VERSION 5.7 ;
  NOWIREEXTENSIONATPIN ON ;
  DIVIDERCHAR "/" ;
  BUSBITCHARS "[]" ;
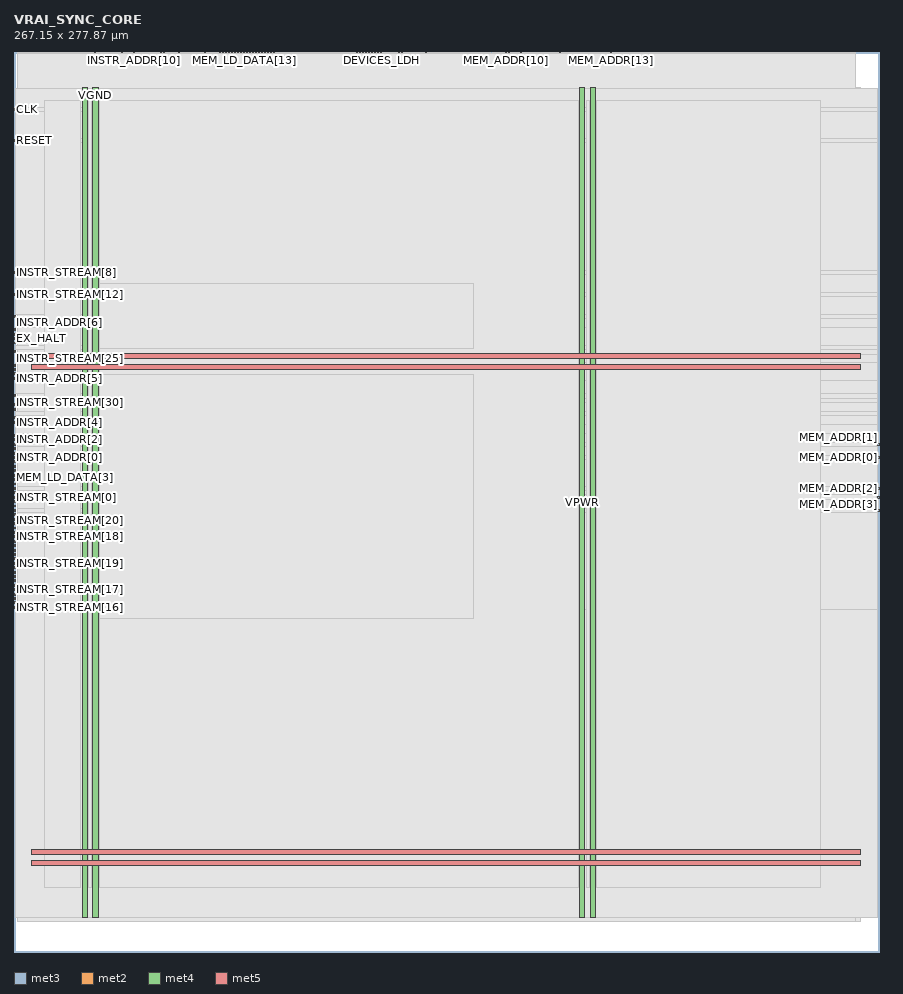
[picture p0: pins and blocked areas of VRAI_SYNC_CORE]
MACRO VRAI_SYNC_CORE
  CLASS BLOCK ;
  FOREIGN VRAI_SYNC_CORE ;
  ORIGIN 0.000 0.000 ;
  SIZE 267.150 BY 277.870 ;
  PIN CLK
    DIRECTION INPUT ;
    USE SIGNAL ;
    ANTENNAGATEAREA 0.852000 ;
    PORT
      LAYER met3 ;
        RECT 0.000 259.800 0.600 260.400 ;
    END
  END CLK
  PIN DEVICES_LDH
    DIRECTION OUTPUT ;
    USE SIGNAL ;
    ANTENNADIFFAREA 0.702900 ;
    PORT
      LAYER met2 ;
        RECT 113.250 277.590 113.530 277.870 ;
    END
  END DEVICES_LDH
  PIN DEVICES_LDW
    DIRECTION OUTPUT ;
    USE SIGNAL ;
    ANTENNADIFFAREA 0.702900 ;
    PORT
      LAYER met2 ;
        RECT 109.570 277.590 109.850 277.870 ;
    END
  END DEVICES_LDW
  PIN DEVICES_STRH
    DIRECTION OUTPUT ;
    USE SIGNAL ;
    ANTENNADIFFAREA 0.702900 ;
    PORT
      LAYER met2 ;
        RECT 112.330 277.590 112.610 277.870 ;
    END
  END DEVICES_STRH
  PIN DEVICES_STRW
    DIRECTION OUTPUT ;
    USE SIGNAL ;
    ANTENNADIFFAREA 0.702900 ;
    PORT
      LAYER met2 ;
        RECT 111.410 277.590 111.690 277.870 ;
    END
  END DEVICES_STRW
  PIN EX_HALT
    DIRECTION OUTPUT ;
    USE SIGNAL ;
    ANTENNADIFFAREA 0.702900 ;
    PORT
      LAYER met3 ;
        RECT 0.000 189.080 0.600 189.680 ;
    END
  END EX_HALT
  PIN INSTR_ADDR[0]
    DIRECTION OUTPUT ;
    USE SIGNAL ;
    ANTENNADIFFAREA 0.702900 ;
    PORT
      LAYER met3 ;
        RECT 0.000 152.360 0.600 152.960 ;
    END
  END INSTR_ADDR[0]
  PIN INSTR_ADDR[10]
    DIRECTION OUTPUT ;
    USE SIGNAL ;
    ANTENNADIFFAREA 0.702900 ;
    PORT
      LAYER met2 ;
        RECT 36.890 277.590 37.170 277.870 ;
    END
  END INSTR_ADDR[10]
  PIN INSTR_ADDR[11]
    DIRECTION OUTPUT ;
    USE SIGNAL ;
    ANTENNADIFFAREA 0.702900 ;
    PORT
      LAYER met2 ;
        RECT 50.690 277.590 50.970 277.870 ;
    END
  END INSTR_ADDR[11]
  PIN INSTR_ADDR[12]
    DIRECTION OUTPUT ;
    USE SIGNAL ;
    ANTENNADIFFAREA 0.702900 ;
    PORT
      LAYER met2 ;
        RECT 58.970 277.590 59.250 277.870 ;
    END
  END INSTR_ADDR[12]
  PIN INSTR_ADDR[13]
    DIRECTION OUTPUT ;
    USE SIGNAL ;
    ANTENNADIFFAREA 0.702900 ;
    PORT
      LAYER met2 ;
        RECT 64.490 277.590 64.770 277.870 ;
    END
  END INSTR_ADDR[13]
  PIN INSTR_ADDR[14]
    DIRECTION OUTPUT ;
    USE SIGNAL ;
    ANTENNADIFFAREA 0.702900 ;
    PORT
      LAYER met2 ;
        RECT 65.410 277.590 65.690 277.870 ;
    END
  END INSTR_ADDR[14]
  PIN INSTR_ADDR[15]
    DIRECTION OUTPUT ;
    USE SIGNAL ;
    ANTENNADIFFAREA 0.702900 ;
    PORT
      LAYER met2 ;
        RECT 63.570 277.590 63.850 277.870 ;
    END
  END INSTR_ADDR[15]
  PIN INSTR_ADDR[1]
    DIRECTION OUTPUT ;
    USE SIGNAL ;
    ANTENNADIFFAREA 0.702900 ;
    PORT
      LAYER met3 ;
        RECT 0.000 151.000 0.600 151.600 ;
    END
  END INSTR_ADDR[1]
  PIN INSTR_ADDR[2]
    DIRECTION OUTPUT ;
    USE SIGNAL ;
    ANTENNADIFFAREA 0.702900 ;
    PORT
      LAYER met3 ;
        RECT 0.000 157.800 0.600 158.400 ;
    END
  END INSTR_ADDR[2]
  PIN INSTR_ADDR[3]
    DIRECTION OUTPUT ;
    USE SIGNAL ;
    ANTENNADIFFAREA 0.702900 ;
    PORT
      LAYER met3 ;
        RECT 0.000 155.080 0.600 155.680 ;
    END
  END INSTR_ADDR[3]
  PIN INSTR_ADDR[4]
    DIRECTION OUTPUT ;
    USE SIGNAL ;
    ANTENNADIFFAREA 0.702900 ;
    PORT
      LAYER met3 ;
        RECT 0.000 163.240 0.600 163.840 ;
    END
  END INSTR_ADDR[4]
  PIN INSTR_ADDR[5]
    DIRECTION OUTPUT ;
    USE SIGNAL ;
    ANTENNADIFFAREA 0.702900 ;
    PORT
      LAYER met3 ;
        RECT 0.000 176.840 0.600 177.440 ;
    END
  END INSTR_ADDR[5]
  PIN INSTR_ADDR[6]
    DIRECTION OUTPUT ;
    USE SIGNAL ;
    ANTENNADIFFAREA 0.702900 ;
    PORT
      LAYER met3 ;
        RECT 0.000 191.800 0.600 192.400 ;
    END
  END INSTR_ADDR[6]
  PIN INSTR_ADDR[7]
    DIRECTION OUTPUT ;
    USE SIGNAL ;
    ANTENNADIFFAREA 0.702900 ;
    PORT
      LAYER met3 ;
        RECT 0.000 195.880 0.600 196.480 ;
    END
  END INSTR_ADDR[7]
  PIN INSTR_ADDR[8]
    DIRECTION OUTPUT ;
    USE SIGNAL ;
    ANTENNADIFFAREA 0.702900 ;
    PORT
      LAYER met2 ;
        RECT 24.930 277.590 25.210 277.870 ;
    END
  END INSTR_ADDR[8]
  PIN INSTR_ADDR[9]
    DIRECTION OUTPUT ;
    USE SIGNAL ;
    ANTENNADIFFAREA 0.702900 ;
    PORT
      LAYER met2 ;
        RECT 33.210 277.590 33.490 277.870 ;
    END
  END INSTR_ADDR[9]
  PIN INSTR_STREAM[0]
    DIRECTION INPUT ;
    USE SIGNAL ;
    ANTENNAGATEAREA 0.213000 ;
    PORT
      LAYER met3 ;
        RECT 0.000 140.120 0.600 140.720 ;
    END
  END INSTR_STREAM[0]
  PIN INSTR_STREAM[10]
    DIRECTION INPUT ;
    USE SIGNAL ;
    ANTENNAGATEAREA 0.213000 ;
    PORT
      LAYER met2 ;
        RECT 66.330 277.590 66.610 277.870 ;
    END
  END INSTR_STREAM[10]
  PIN INSTR_STREAM[11]
    DIRECTION INPUT ;
    USE SIGNAL ;
    ANTENNAGATEAREA 0.213000 ;
    PORT
      LAYER met2 ;
        RECT 71.850 277.590 72.130 277.870 ;
    END
  END INSTR_STREAM[11]
  PIN INSTR_STREAM[12]
    DIRECTION INPUT ;
    USE SIGNAL ;
    ANTENNAGATEAREA 0.213000 ;
    PORT
      LAYER met3 ;
        RECT 0.000 202.680 0.600 203.280 ;
    END
  END INSTR_STREAM[12]
  PIN INSTR_STREAM[13]
    DIRECTION INPUT ;
    USE SIGNAL ;
    ANTENNAGATEAREA 0.213000 ;
    PORT
      LAYER met2 ;
        RECT 67.250 277.590 67.530 277.870 ;
    END
  END INSTR_STREAM[13]
  PIN INSTR_STREAM[14]
    DIRECTION INPUT ;
    USE SIGNAL ;
    ANTENNAGATEAREA 0.213000 ;
    PORT
      LAYER met3 ;
        RECT 0.000 187.720 0.600 188.320 ;
    END
  END INSTR_STREAM[14]
  PIN INSTR_STREAM[15]
    DIRECTION INPUT ;
    USE SIGNAL ;
    ANTENNAGATEAREA 0.213000 ;
    PORT
      LAYER met2 ;
        RECT 76.450 277.590 76.730 277.870 ;
    END
  END INSTR_STREAM[15]
  PIN INSTR_STREAM[16]
    DIRECTION INPUT ;
    USE SIGNAL ;
    ANTENNAGATEAREA 0.213000 ;
    PORT
      LAYER met3 ;
        RECT 0.000 106.120 0.600 106.720 ;
    END
  END INSTR_STREAM[16]
  PIN INSTR_STREAM[17]
    DIRECTION INPUT ;
    USE SIGNAL ;
    ANTENNAGATEAREA 0.213000 ;
    PORT
      LAYER met3 ;
        RECT 0.000 111.560 0.600 112.160 ;
    END
  END INSTR_STREAM[17]
  PIN INSTR_STREAM[18]
    DIRECTION INPUT ;
    USE SIGNAL ;
    ANTENNAGATEAREA 0.213000 ;
    PORT
      LAYER met3 ;
        RECT 0.000 127.880 0.600 128.480 ;
    END
  END INSTR_STREAM[18]
  PIN INSTR_STREAM[19]
    DIRECTION INPUT ;
    USE SIGNAL ;
    ANTENNAGATEAREA 0.213000 ;
    PORT
      LAYER met3 ;
        RECT 0.000 119.720 0.600 120.320 ;
    END
  END INSTR_STREAM[19]
  PIN INSTR_STREAM[1]
    DIRECTION INPUT ;
    USE SIGNAL ;
    ANTENNAGATEAREA 0.213000 ;
    PORT
      LAYER met3 ;
        RECT 0.000 129.240 0.600 129.840 ;
    END
  END INSTR_STREAM[1]
  PIN INSTR_STREAM[20]
    DIRECTION INPUT ;
    USE SIGNAL ;
    ANTENNAGATEAREA 0.213000 ;
    PORT
      LAYER met3 ;
        RECT 0.000 130.600 0.600 131.200 ;
    END
  END INSTR_STREAM[20]
  PIN INSTR_STREAM[21]
    DIRECTION INPUT ;
    USE SIGNAL ;
    ANTENNAGATEAREA 0.213000 ;
    PORT
      LAYER met3 ;
        RECT 0.000 131.960 0.600 132.560 ;
    END
  END INSTR_STREAM[21]
  PIN INSTR_STREAM[22]
    DIRECTION INPUT ;
    USE SIGNAL ;
    ANTENNAGATEAREA 0.213000 ;
    PORT
      LAYER met3 ;
        RECT 0.000 125.160 0.600 125.760 ;
    END
  END INSTR_STREAM[22]
  PIN INSTR_STREAM[23]
    DIRECTION INPUT ;
    USE SIGNAL ;
    ANTENNAGATEAREA 0.213000 ;
    PORT
      LAYER met3 ;
        RECT 0.000 136.040 0.600 136.640 ;
    END
  END INSTR_STREAM[23]
  PIN INSTR_STREAM[24]
    DIRECTION INPUT ;
    USE SIGNAL ;
    ANTENNAGATEAREA 0.213000 ;
    PORT
      LAYER met2 ;
        RECT 73.690 277.590 73.970 277.870 ;
    END
  END INSTR_STREAM[24]
  PIN INSTR_STREAM[25]
    DIRECTION INPUT ;
    USE SIGNAL ;
    ANTENNAGATEAREA 0.213000 ;
    PORT
      LAYER met3 ;
        RECT 0.000 185.000 0.600 185.600 ;
    END
  END INSTR_STREAM[25]
  PIN INSTR_STREAM[26]
    DIRECTION INPUT ;
    USE SIGNAL ;
    ANTENNAGATEAREA 0.213000 ;
    PORT
      LAYER met2 ;
        RECT 74.610 277.590 74.890 277.870 ;
    END
  END INSTR_STREAM[26]
  PIN INSTR_STREAM[27]
    DIRECTION INPUT ;
    USE SIGNAL ;
    ANTENNAGATEAREA 0.213000 ;
    PORT
      LAYER met2 ;
        RECT 72.770 277.590 73.050 277.870 ;
    END
  END INSTR_STREAM[27]
  PIN INSTR_STREAM[28]
    DIRECTION INPUT ;
    USE SIGNAL ;
    ANTENNAGATEAREA 0.213000 ;
    PORT
      LAYER met3 ;
        RECT 0.000 159.160 0.600 159.760 ;
    END
  END INSTR_STREAM[28]
  PIN INSTR_STREAM[29]
    DIRECTION INPUT ;
    USE SIGNAL ;
    ANTENNAGATEAREA 0.213000 ;
    PORT
      LAYER met3 ;
        RECT 0.000 156.440 0.600 157.040 ;
    END
  END INSTR_STREAM[29]
  PIN INSTR_STREAM[2]
    DIRECTION INPUT ;
    USE SIGNAL ;
    ANTENNAGATEAREA 0.213000 ;
    PORT
      LAYER met3 ;
        RECT 0.000 138.760 0.600 139.360 ;
    END
  END INSTR_STREAM[2]
  PIN INSTR_STREAM[30]
    DIRECTION INPUT ;
    USE SIGNAL ;
    ANTENNAGATEAREA 0.213000 ;
    PORT
      LAYER met3 ;
        RECT 0.000 167.320 0.600 167.920 ;
    END
  END INSTR_STREAM[30]
  PIN INSTR_STREAM[31]
    DIRECTION INPUT ;
    USE SIGNAL ;
    ANTENNAGATEAREA 0.213000 ;
    PORT
      LAYER met3 ;
        RECT 0.000 164.600 0.600 165.200 ;
    END
  END INSTR_STREAM[31]
  PIN INSTR_STREAM[3]
    DIRECTION INPUT ;
    USE SIGNAL ;
    ANTENNAGATEAREA 0.213000 ;
    PORT
      LAYER met3 ;
        RECT 0.000 137.400 0.600 138.000 ;
    END
  END INSTR_STREAM[3]
  PIN INSTR_STREAM[4]
    DIRECTION INPUT ;
    USE SIGNAL ;
    ANTENNAGATEAREA 0.213000 ;
    PORT
      LAYER met3 ;
        RECT 0.000 149.640 0.600 150.240 ;
    END
  END INSTR_STREAM[4]
  PIN INSTR_STREAM[5]
    DIRECTION INPUT ;
    USE SIGNAL ;
    ANTENNAGATEAREA 0.213000 ;
    PORT
      LAYER met3 ;
        RECT 0.000 178.200 0.600 178.800 ;
    END
  END INSTR_STREAM[5]
  PIN INSTR_STREAM[6]
    DIRECTION INPUT ;
    USE SIGNAL ;
    ANTENNAGATEAREA 0.213000 ;
    PORT
      LAYER met2 ;
        RECT 46.090 277.590 46.370 277.870 ;
    END
  END INSTR_STREAM[6]
  PIN INSTR_STREAM[7]
    DIRECTION INPUT ;
    USE SIGNAL ;
    ANTENNAGATEAREA 0.213000 ;
    PORT
      LAYER met3 ;
        RECT 0.000 190.440 0.600 191.040 ;
    END
  END INSTR_STREAM[7]
  PIN INSTR_STREAM[8]
    DIRECTION INPUT ;
    USE SIGNAL ;
    ANTENNAGATEAREA 0.213000 ;
    PORT
      LAYER met3 ;
        RECT 0.000 209.480 0.600 210.080 ;
    END
  END INSTR_STREAM[8]
  PIN INSTR_STREAM[9]
    DIRECTION INPUT ;
    USE SIGNAL ;
    ANTENNAGATEAREA 0.213000 ;
    PORT
      LAYER met2 ;
        RECT 45.170 277.590 45.450 277.870 ;
    END
  END INSTR_STREAM[9]
  PIN INVALID_MEM
    DIRECTION OUTPUT ;
    USE SIGNAL ;
    ANTENNADIFFAREA 0.702900 ;
    PORT
      LAYER met3 ;
        RECT 0.000 180.920 0.600 181.520 ;
    END
  END INVALID_MEM
  PIN MAIN_LDH
    DIRECTION OUTPUT ;
    USE SIGNAL ;
    ANTENNADIFFAREA 0.702900 ;
    PORT
      LAYER met2 ;
        RECT 105.890 277.590 106.170 277.870 ;
    END
  END MAIN_LDH
  PIN MAIN_LDW
    DIRECTION OUTPUT ;
    USE SIGNAL ;
    ANTENNADIFFAREA 0.702900 ;
    PORT
      LAYER met2 ;
        RECT 106.810 277.590 107.090 277.870 ;
    END
  END MAIN_LDW
  PIN MAIN_STRH
    DIRECTION OUTPUT ;
    USE SIGNAL ;
    ANTENNADIFFAREA 0.702900 ;
    PORT
      LAYER met2 ;
        RECT 108.650 277.590 108.930 277.870 ;
    END
  END MAIN_STRH
  PIN MAIN_STRW
    DIRECTION OUTPUT ;
    USE SIGNAL ;
    ANTENNADIFFAREA 0.702900 ;
    PORT
      LAYER met2 ;
        RECT 107.730 277.590 108.010 277.870 ;
    END
  END MAIN_STRW
  PIN MEM_ADDR[0]
    DIRECTION OUTPUT ;
    USE SIGNAL ;
    ANTENNADIFFAREA 0.702900 ;
    PORT
      LAYER met3 ;
        RECT 266.550 152.360 267.150 152.960 ;
    END
  END MEM_ADDR[0]
  PIN MEM_ADDR[10]
    DIRECTION OUTPUT ;
    USE SIGNAL ;
    ANTENNADIFFAREA 0.702900 ;
    PORT
      LAYER met2 ;
        RECT 151.890 277.590 152.170 277.870 ;
    END
  END MEM_ADDR[10]
  PIN MEM_ADDR[11]
    DIRECTION OUTPUT ;
    USE SIGNAL ;
    ANTENNADIFFAREA 0.702900 ;
    PORT
      LAYER met2 ;
        RECT 127.050 277.590 127.330 277.870 ;
    END
  END MEM_ADDR[11]
  PIN MEM_ADDR[12]
    DIRECTION OUTPUT ;
    USE SIGNAL ;
    ANTENNADIFFAREA 0.702900 ;
    PORT
      LAYER met2 ;
        RECT 156.490 277.590 156.770 277.870 ;
    END
  END MEM_ADDR[12]
  PIN MEM_ADDR[13]
    DIRECTION OUTPUT ;
    USE SIGNAL ;
    ANTENNADIFFAREA 0.702900 ;
    PORT
      LAYER met2 ;
        RECT 184.090 277.590 184.370 277.870 ;
    END
  END MEM_ADDR[13]
  PIN MEM_ADDR[14]
    DIRECTION OUTPUT ;
    USE SIGNAL ;
    ANTENNADIFFAREA 0.702900 ;
    PORT
      LAYER met2 ;
        RECT 168.450 277.590 168.730 277.870 ;
    END
  END MEM_ADDR[14]
  PIN MEM_ADDR[15]
    DIRECTION OUTPUT ;
    USE SIGNAL ;
    ANTENNADIFFAREA 0.702900 ;
    PORT
      LAYER met2 ;
        RECT 110.490 277.590 110.770 277.870 ;
    END
  END MEM_ADDR[15]
  PIN MEM_ADDR[1]
    DIRECTION OUTPUT ;
    USE SIGNAL ;
    ANTENNADIFFAREA 0.702900 ;
    PORT
      LAYER met3 ;
        RECT 266.550 156.440 267.150 157.040 ;
    END
  END MEM_ADDR[1]
  PIN MEM_ADDR[2]
    DIRECTION OUTPUT ;
    USE SIGNAL ;
    ANTENNADIFFAREA 0.702900 ;
    PORT
      LAYER met3 ;
        RECT 266.550 142.840 267.150 143.440 ;
    END
  END MEM_ADDR[2]
  PIN MEM_ADDR[3]
    DIRECTION OUTPUT ;
    USE SIGNAL ;
    ANTENNADIFFAREA 0.702900 ;
    PORT
      LAYER met3 ;
        RECT 266.550 140.120 267.150 140.720 ;
    END
  END MEM_ADDR[3]
  PIN MEM_ADDR[4]
    DIRECTION OUTPUT ;
    USE SIGNAL ;
    ANTENNADIFFAREA 0.702900 ;
    PORT
      LAYER met3 ;
        RECT 266.550 136.040 267.150 136.640 ;
    END
  END MEM_ADDR[4]
  PIN MEM_ADDR[5]
    DIRECTION OUTPUT ;
    USE SIGNAL ;
    ANTENNADIFFAREA 0.702900 ;
    PORT
      LAYER met3 ;
        RECT 0.000 153.720 0.600 154.320 ;
    END
  END MEM_ADDR[5]
  PIN MEM_ADDR[6]
    DIRECTION OUTPUT ;
    USE SIGNAL ;
    ANTENNADIFFAREA 0.702900 ;
    PORT
      LAYER met2 ;
        RECT 147.290 277.590 147.570 277.870 ;
    END
  END MEM_ADDR[6]
  PIN MEM_ADDR[7]
    DIRECTION OUTPUT ;
    USE SIGNAL ;
    ANTENNADIFFAREA 0.702900 ;
    PORT
      LAYER met2 ;
        RECT 119.690 277.590 119.970 277.870 ;
    END
  END MEM_ADDR[7]
  PIN MEM_ADDR[8]
    DIRECTION OUTPUT ;
    USE SIGNAL ;
    ANTENNADIFFAREA 0.702900 ;
    PORT
      LAYER met2 ;
        RECT 118.770 277.590 119.050 277.870 ;
    END
  END MEM_ADDR[8]
  PIN MEM_ADDR[9]
    DIRECTION OUTPUT ;
    USE SIGNAL ;
    ANTENNADIFFAREA 0.702900 ;
    PORT
      LAYER met2 ;
        RECT 152.810 277.590 153.090 277.870 ;
    END
  END MEM_ADDR[9]
  PIN MEM_LD_DATA[0]
    DIRECTION INPUT ;
    USE SIGNAL ;
    ANTENNAGATEAREA 0.213000 ;
    PORT
      LAYER met3 ;
        RECT 0.000 144.200 0.600 144.800 ;
    END
  END MEM_LD_DATA[0]
  PIN MEM_LD_DATA[10]
    DIRECTION INPUT ;
    USE SIGNAL ;
    ANTENNAGATEAREA 0.213000 ;
    PORT
      LAYER met2 ;
        RECT 77.370 277.590 77.650 277.870 ;
    END
  END MEM_LD_DATA[10]
  PIN MEM_LD_DATA[11]
    DIRECTION INPUT ;
    USE SIGNAL ;
    ANTENNAGATEAREA 0.213000 ;
    PORT
      LAYER met2 ;
        RECT 75.530 277.590 75.810 277.870 ;
    END
  END MEM_LD_DATA[11]
  PIN MEM_LD_DATA[12]
    DIRECTION INPUT ;
    USE SIGNAL ;
    ANTENNAGATEAREA 0.213000 ;
    PORT
      LAYER met2 ;
        RECT 68.170 277.590 68.450 277.870 ;
    END
  END MEM_LD_DATA[12]
  PIN MEM_LD_DATA[13]
    DIRECTION INPUT ;
    USE SIGNAL ;
    ANTENNAGATEAREA 0.213000 ;
    PORT
      LAYER met2 ;
        RECT 70.930 277.590 71.210 277.870 ;
    END
  END MEM_LD_DATA[13]
  PIN MEM_LD_DATA[14]
    DIRECTION INPUT ;
    USE SIGNAL ;
    ANTENNAGATEAREA 0.213000 ;
    PORT
      LAYER met2 ;
        RECT 79.210 277.590 79.490 277.870 ;
    END
  END MEM_LD_DATA[14]
  PIN MEM_LD_DATA[15]
    DIRECTION INPUT ;
    USE SIGNAL ;
    ANTENNAGATEAREA 0.213000 ;
    PORT
      LAYER met2 ;
        RECT 80.130 277.590 80.410 277.870 ;
    END
  END MEM_LD_DATA[15]
  PIN MEM_LD_DATA[1]
    DIRECTION INPUT ;
    USE SIGNAL ;
    ANTENNAGATEAREA 0.213000 ;
    PORT
      LAYER met3 ;
        RECT 0.000 146.920 0.600 147.520 ;
    END
  END MEM_LD_DATA[1]
  PIN MEM_LD_DATA[2]
    DIRECTION INPUT ;
    USE SIGNAL ;
    ANTENNAGATEAREA 0.213000 ;
    PORT
      LAYER met3 ;
        RECT 0.000 171.400 0.600 172.000 ;
    END
  END MEM_LD_DATA[2]
  PIN MEM_LD_DATA[3]
    DIRECTION INPUT ;
    USE SIGNAL ;
    ANTENNAGATEAREA 0.213000 ;
    PORT
      LAYER met3 ;
        RECT 0.000 148.280 0.600 148.880 ;
    END
  END MEM_LD_DATA[3]
  PIN MEM_LD_DATA[4]
    DIRECTION INPUT ;
    USE SIGNAL ;
    ANTENNAGATEAREA 0.213000 ;
    PORT
      LAYER met3 ;
        RECT 0.000 145.560 0.600 146.160 ;
    END
  END MEM_LD_DATA[4]
  PIN MEM_LD_DATA[5]
    DIRECTION INPUT ;
    USE SIGNAL ;
    ANTENNAGATEAREA 0.213000 ;
    PORT
      LAYER met3 ;
        RECT 0.000 168.680 0.600 169.280 ;
    END
  END MEM_LD_DATA[5]
  PIN MEM_LD_DATA[6]
    DIRECTION INPUT ;
    USE SIGNAL ;
    ANTENNAGATEAREA 0.213000 ;
    PORT
      LAYER met3 ;
        RECT 0.000 179.560 0.600 180.160 ;
    END
  END MEM_LD_DATA[6]
  PIN MEM_LD_DATA[7]
    DIRECTION INPUT ;
    USE SIGNAL ;
    ANTENNAGATEAREA 0.213000 ;
    PORT
      LAYER met2 ;
        RECT 70.010 277.590 70.290 277.870 ;
    END
  END MEM_LD_DATA[7]
  PIN MEM_LD_DATA[8]
    DIRECTION INPUT ;
    USE SIGNAL ;
    ANTENNAGATEAREA 0.213000 ;
    PORT
      LAYER met2 ;
        RECT 78.290 277.590 78.570 277.870 ;
    END
  END MEM_LD_DATA[8]
  PIN MEM_LD_DATA[9]
    DIRECTION INPUT ;
    USE SIGNAL ;
    ANTENNAGATEAREA 0.213000 ;
    PORT
      LAYER met2 ;
        RECT 69.090 277.590 69.370 277.870 ;
    END
  END MEM_LD_DATA[9]
  PIN MEM_STR_DATA[0]
    DIRECTION OUTPUT ;
    USE SIGNAL ;
    ANTENNADIFFAREA 0.702900 ;
    PORT
      LAYER met3 ;
        RECT 0.000 108.840 0.600 109.440 ;
    END
  END MEM_STR_DATA[0]
  PIN MEM_STR_DATA[10]
    DIRECTION OUTPUT ;
    USE SIGNAL ;
    ANTENNADIFFAREA 0.702900 ;
    PORT
      LAYER met3 ;
        RECT 0.000 115.640 0.600 116.240 ;
    END
  END MEM_STR_DATA[10]
  PIN MEM_STR_DATA[11]
    DIRECTION OUTPUT ;
    USE SIGNAL ;
    ANTENNADIFFAREA 0.702900 ;
    PORT
      LAYER met3 ;
        RECT 0.000 117.000 0.600 117.600 ;
    END
  END MEM_STR_DATA[11]
  PIN MEM_STR_DATA[12]
    DIRECTION OUTPUT ;
    USE SIGNAL ;
    ANTENNADIFFAREA 0.702900 ;
    PORT
      LAYER met3 ;
        RECT 0.000 110.200 0.600 110.800 ;
    END
  END MEM_STR_DATA[12]
  PIN MEM_STR_DATA[13]
    DIRECTION OUTPUT ;
    USE SIGNAL ;
    ANTENNADIFFAREA 0.702900 ;
    PORT
      LAYER met3 ;
        RECT 0.000 133.320 0.600 133.920 ;
    END
  END MEM_STR_DATA[13]
  PIN MEM_STR_DATA[14]
    DIRECTION OUTPUT ;
    USE SIGNAL ;
    ANTENNADIFFAREA 0.702900 ;
    PORT
      LAYER met3 ;
        RECT 0.000 134.680 0.600 135.280 ;
    END
  END MEM_STR_DATA[14]
  PIN MEM_STR_DATA[15]
    DIRECTION OUTPUT ;
    USE SIGNAL ;
    ANTENNADIFFAREA 0.702900 ;
    PORT
      LAYER met3 ;
        RECT 0.000 122.440 0.600 123.040 ;
    END
  END MEM_STR_DATA[15]
  PIN MEM_STR_DATA[1]
    DIRECTION OUTPUT ;
    USE SIGNAL ;
    ANTENNADIFFAREA 0.702900 ;
    PORT
      LAYER met3 ;
        RECT 0.000 114.280 0.600 114.880 ;
    END
  END MEM_STR_DATA[1]
  PIN MEM_STR_DATA[2]
    DIRECTION OUTPUT ;
    USE SIGNAL ;
    ANTENNADIFFAREA 0.702900 ;
    PORT
      LAYER met3 ;
        RECT 0.000 142.840 0.600 143.440 ;
    END
  END MEM_STR_DATA[2]
  PIN MEM_STR_DATA[3]
    DIRECTION OUTPUT ;
    USE SIGNAL ;
    ANTENNADIFFAREA 0.702900 ;
    PORT
      LAYER met3 ;
        RECT 0.000 121.080 0.600 121.680 ;
    END
  END MEM_STR_DATA[3]
  PIN MEM_STR_DATA[4]
    DIRECTION OUTPUT ;
    USE SIGNAL ;
    ANTENNADIFFAREA 0.702900 ;
    PORT
      LAYER met3 ;
        RECT 0.000 118.360 0.600 118.960 ;
    END
  END MEM_STR_DATA[4]
  PIN MEM_STR_DATA[5]
    DIRECTION OUTPUT ;
    USE SIGNAL ;
    ANTENNADIFFAREA 0.702900 ;
    PORT
      LAYER met3 ;
        RECT 0.000 123.800 0.600 124.400 ;
    END
  END MEM_STR_DATA[5]
  PIN MEM_STR_DATA[6]
    DIRECTION OUTPUT ;
    USE SIGNAL ;
    ANTENNADIFFAREA 0.702900 ;
    PORT
      LAYER met3 ;
        RECT 0.000 141.480 0.600 142.080 ;
    END
  END MEM_STR_DATA[6]
  PIN MEM_STR_DATA[7]
    DIRECTION OUTPUT ;
    USE SIGNAL ;
    ANTENNADIFFAREA 0.702900 ;
    PORT
      LAYER met3 ;
        RECT 0.000 112.920 0.600 113.520 ;
    END
  END MEM_STR_DATA[7]
  PIN MEM_STR_DATA[8]
    DIRECTION OUTPUT ;
    USE SIGNAL ;
    ANTENNADIFFAREA 0.702900 ;
    PORT
      LAYER met3 ;
        RECT 0.000 107.480 0.600 108.080 ;
    END
  END MEM_STR_DATA[8]
  PIN MEM_STR_DATA[9]
    DIRECTION OUTPUT ;
    USE SIGNAL ;
    ANTENNADIFFAREA 0.702900 ;
    PORT
      LAYER met3 ;
        RECT 0.000 126.520 0.600 127.120 ;
    END
  END MEM_STR_DATA[9]
  PIN RESET
    DIRECTION INPUT ;
    USE SIGNAL ;
    ANTENNAGATEAREA 0.247500 ;
    PORT
      LAYER met3 ;
        RECT 0.000 250.280 0.600 250.880 ;
    END
  END RESET
  PIN VGND
    DIRECTION INOUT ;
    USE GROUND ;
    PORT
      LAYER met4 ;
        RECT 24.340 10.640 25.940 266.800 ;
    END
    PORT
      LAYER met4 ;
        RECT 177.940 10.640 179.540 266.800 ;
    END
    PORT
      LAYER met5 ;
        RECT 5.520 30.030 261.280 31.630 ;
    END
    PORT
      LAYER met5 ;
        RECT 5.520 183.210 261.280 184.810 ;
    END
  END VGND
  PIN VPWR
    DIRECTION INOUT ;
    USE POWER ;
    PORT
      LAYER met4 ;
        RECT 21.040 10.640 22.640 266.800 ;
    END
    PORT
      LAYER met4 ;
        RECT 174.640 10.640 176.240 266.800 ;
    END
    PORT
      LAYER met5 ;
        RECT 5.520 26.730 261.280 28.330 ;
    END
    PORT
      LAYER met5 ;
        RECT 5.520 179.910 261.280 181.510 ;
    END
  END VPWR
  OBS
      LAYER nwell ;
        RECT 5.330 10.795 261.470 266.645 ;
      LAYER li1 ;
        RECT 5.520 10.795 261.280 266.645 ;
      LAYER met1 ;
        RECT 0.990 9.560 261.280 266.800 ;
      LAYER met2 ;
        RECT 1.010 277.310 24.650 277.590 ;
        RECT 25.490 277.310 32.930 277.590 ;
        RECT 33.770 277.310 36.610 277.590 ;
        RECT 37.450 277.310 44.890 277.590 ;
        RECT 45.730 277.310 45.810 277.590 ;
        RECT 46.650 277.310 50.410 277.590 ;
        RECT 51.250 277.310 58.690 277.590 ;
        RECT 59.530 277.310 63.290 277.590 ;
        RECT 64.130 277.310 64.210 277.590 ;
        RECT 65.050 277.310 65.130 277.590 ;
        RECT 65.970 277.310 66.050 277.590 ;
        RECT 66.890 277.310 66.970 277.590 ;
        RECT 67.810 277.310 67.890 277.590 ;
        RECT 68.730 277.310 68.810 277.590 ;
        RECT 69.650 277.310 69.730 277.590 ;
        RECT 70.570 277.310 70.650 277.590 ;
        RECT 71.490 277.310 71.570 277.590 ;
        RECT 72.410 277.310 72.490 277.590 ;
        RECT 73.330 277.310 73.410 277.590 ;
        RECT 74.250 277.310 74.330 277.590 ;
        RECT 75.170 277.310 75.250 277.590 ;
        RECT 76.090 277.310 76.170 277.590 ;
        RECT 77.010 277.310 77.090 277.590 ;
        RECT 77.930 277.310 78.010 277.590 ;
        RECT 78.850 277.310 78.930 277.590 ;
        RECT 79.770 277.310 79.850 277.590 ;
        RECT 80.690 277.310 105.610 277.590 ;
        RECT 106.450 277.310 106.530 277.590 ;
        RECT 107.370 277.310 107.450 277.590 ;
        RECT 108.290 277.310 108.370 277.590 ;
        RECT 109.210 277.310 109.290 277.590 ;
        RECT 110.130 277.310 110.210 277.590 ;
        RECT 111.050 277.310 111.130 277.590 ;
        RECT 111.970 277.310 112.050 277.590 ;
        RECT 112.890 277.310 112.970 277.590 ;
        RECT 113.810 277.310 118.490 277.590 ;
        RECT 119.330 277.310 119.410 277.590 ;
        RECT 120.250 277.310 126.770 277.590 ;
        RECT 127.610 277.310 147.010 277.590 ;
        RECT 147.850 277.310 151.610 277.590 ;
        RECT 152.450 277.310 152.530 277.590 ;
        RECT 153.370 277.310 156.210 277.590 ;
        RECT 157.050 277.310 168.170 277.590 ;
        RECT 169.010 277.310 183.810 277.590 ;
        RECT 184.650 277.310 259.810 277.590 ;
        RECT 1.010 9.530 259.810 277.310 ;
      LAYER met3 ;
        RECT 0.600 260.800 266.550 266.725 ;
        RECT 1.000 259.400 266.550 260.800 ;
        RECT 0.600 251.280 266.550 259.400 ;
        RECT 1.000 249.880 266.550 251.280 ;
        RECT 0.600 210.480 266.550 249.880 ;
        RECT 1.000 209.080 266.550 210.480 ;
        RECT 0.600 203.680 266.550 209.080 ;
        RECT 1.000 202.280 266.550 203.680 ;
        RECT 0.600 196.880 266.550 202.280 ;
        RECT 1.000 195.480 266.550 196.880 ;
        RECT 0.600 192.800 266.550 195.480 ;
        RECT 1.000 187.320 266.550 192.800 ;
        RECT 0.600 186.000 266.550 187.320 ;
        RECT 1.000 184.600 266.550 186.000 ;
        RECT 0.600 181.920 266.550 184.600 ;
        RECT 1.000 176.440 266.550 181.920 ;
        RECT 0.600 172.400 266.550 176.440 ;
        RECT 1.000 171.000 266.550 172.400 ;
        RECT 0.600 169.680 266.550 171.000 ;
        RECT 1.000 166.920 266.550 169.680 ;
        RECT 0.600 165.600 266.550 166.920 ;
        RECT 1.000 162.840 266.550 165.600 ;
        RECT 0.600 160.160 266.550 162.840 ;
        RECT 1.000 157.440 266.550 160.160 ;
        RECT 1.000 156.040 266.150 157.440 ;
        RECT 1.000 153.360 266.550 156.040 ;
        RECT 1.000 151.960 266.150 153.360 ;
        RECT 1.000 143.840 266.550 151.960 ;
        RECT 1.000 142.440 266.150 143.840 ;
        RECT 1.000 141.120 266.550 142.440 ;
        RECT 1.000 139.720 266.150 141.120 ;
        RECT 1.000 137.040 266.550 139.720 ;
        RECT 1.000 135.640 266.150 137.040 ;
        RECT 1.000 105.720 266.550 135.640 ;
        RECT 0.600 10.715 266.550 105.720 ;
      LAYER met4 ;
        RECT 9.495 19.895 20.640 262.985 ;
        RECT 23.040 19.895 23.940 262.985 ;
        RECT 26.340 19.895 174.240 262.985 ;
        RECT 176.640 19.895 177.540 262.985 ;
        RECT 179.940 19.895 249.025 262.985 ;
      LAYER met5 ;
        RECT 26.340 186.410 142.020 206.500 ;
        RECT 26.340 102.900 142.020 178.310 ;
  END
END VRAI_SYNC_CORE
END LIBRARY

